VERSION 5.7 ;
  NOWIREEXTENSIONATPIN ON ;
  DIVIDERCHAR "/" ;
  BUSBITCHARS "[]" ;
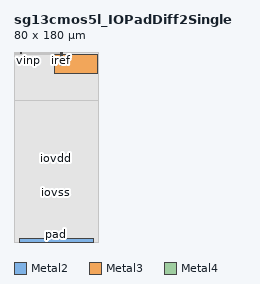
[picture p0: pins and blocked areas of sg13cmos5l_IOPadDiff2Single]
MACRO sg13cmos5l_IOPadDiff2Single
  CLASS PAD INOUT ;
  FOREIGN sg13cmos5l_IOPadDiff2Single ;
  ORIGIN 0.000 0.000 ;
  SIZE 80.000 BY 180.000 ;
  PIN pad
    ANTENNAGATEAREA 40.000000 ;
    ANTENNADIFFAREA 838.224792 ;
    PORT
      LAYER Metal2 ;
        RECT 5.000 0.000 75.000 3.000 ;
    END
  END pad
  PIN vinp
    ANTENNAGATEAREA 20.000000 ;
    PORT
      LAYER Metal2 ;
        RECT 6.060 179.430 6.350 180.000 ;
    END
  END vinp
  PIN vinn
    ANTENNAGATEAREA 20.000000 ;
    PORT
      LAYER Metal2 ;
        RECT 6.600 178.890 6.890 180.000 ;
    END
  END vinn
  PIN vref
    ANTENNAGATEAREA 80.000000 ;
    PORT
      LAYER Metal2 ;
        RECT 7.140 178.350 7.430 180.000 ;
    END
  END vref
  PIN iref
    ANTENNADIFFAREA 0.680000 ;
    PORT
      LAYER Metal2 ;
        RECT 44.400 167.300 44.690 180.000 ;
    END
  END iref
  PIN en_3v3_b
    ANTENNAGATEAREA 1.800000 ;
    PORT
      LAYER Metal2 ;
        RECT 44.940 168.065 45.230 180.000 ;
    END
  END en_3v3_b
  PIN en_3v3
    ANTENNAGATEAREA 1.350000 ;
    PORT
      LAYER Metal2 ;
        RECT 45.480 168.605 45.770 180.000 ;
    END
  END en_3v3
  PIN iovdd
    ANTENNAGATEAREA 95.984001 ;
    ANTENNADIFFAREA 989.417603 ;
    PORT
      LAYER Metal3 ;
        RECT 39.900 78.650 40.100 78.850 ;
      LAYER Metal4 ;
        RECT 39.900 78.650 40.100 78.850 ;
    END
  END iovdd
  PIN iovss
    ANTENNAGATEAREA 8.800000 ;
    ANTENNADIFFAREA 957.626404 ;
    PORT
      LAYER Metal3 ;
        RECT 39.900 47.150 40.100 47.350 ;
      LAYER Metal4 ;
        RECT 39.900 47.150 40.100 47.350 ;
    END
  END iovss
  PIN vdd
    ANTENNADIFFAREA 0.306000 ;
    PORT
      LAYER Metal3 ;
        RECT 38.755 160.000 79.540 178.000 ;
    END
  END vdd
  OBS
      LAYER GatPoly ;
        RECT 0.000 6.000 80.000 177.815 ;
      LAYER Metal1 ;
        RECT 0.000 6.000 80.000 177.810 ;
      LAYER Metal2 ;
        RECT 0.100 179.220 5.850 179.720 ;
        RECT 0.100 178.680 6.390 179.220 ;
        RECT 0.100 178.140 6.930 178.680 ;
        RECT 7.640 178.140 44.190 179.720 ;
        RECT 0.100 167.090 44.190 178.140 ;
        RECT 45.980 168.395 79.900 179.720 ;
        RECT 45.440 167.855 79.900 168.395 ;
        RECT 44.900 167.090 79.900 167.855 ;
        RECT 0.100 3.210 79.900 167.090 ;
        RECT 0.100 3.000 4.790 3.210 ;
        RECT 75.210 3.000 79.900 3.210 ;
      LAYER Metal3 ;
        RECT 0.000 159.790 38.545 178.000 ;
        RECT 79.750 159.790 80.000 178.000 ;
        RECT 0.000 79.060 80.000 159.790 ;
        RECT 0.000 78.440 39.690 79.060 ;
        RECT 40.310 78.440 80.000 79.060 ;
        RECT 0.000 47.560 80.000 78.440 ;
        RECT 0.000 46.940 39.690 47.560 ;
        RECT 40.310 46.940 80.000 47.560 ;
        RECT 0.000 0.000 80.000 46.940 ;
      LAYER Metal4 ;
        RECT 0.000 0.000 80.000 178.000 ;
      LAYER TopMetal1 ;
        RECT 0.000 0.000 80.000 134.000 ;
  END
END sg13cmos5l_IOPadDiff2Single
END LIBRARY

